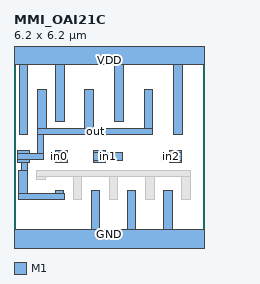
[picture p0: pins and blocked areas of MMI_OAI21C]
MACRO MMI_OAI21C
	CLASS CORE ;
	FOREIGN MMI_OAI21C 0 0 ;
	SIZE 6.2 BY 6.2 ;
	SYMMETRY X Y ;
	SITE CORE1 ;
	PIN out
		DIRECTION output ;
		USE SIGNAL ;
		PORT
			LAYER M1 ;
			RECT 0.765 3.7 1.045 4.98 ;
			LAYER M1 ;
			RECT 2.315 3.7 2.595 4.98 ;
			LAYER M1 ;
			RECT 4.245 3.7 4.525 4.98 ;
			LAYER M1 ;
			RECT 0.765 3.505 4.525 3.7 ;
			LAYER M1 ;
			RECT 0.12 2.885 0.5 2.98 ;
			LAYER M1 ;
			RECT 0.765 2.885 0.955 3.505 ;
			LAYER M1 ;
			RECT 0.12 2.695 0.955 2.885 ;
			LAYER M1 ;
			RECT 0.12 2.6 0.5 2.695 ;
			LAYER M1 ;
			RECT 0.245 2.34 0.435 2.6 ;
			LAYER M1 ;
			RECT 0.16 1.575 0.44 2.34 ;
			LAYER M1 ;
			RECT 1.34 1.575 1.62 1.665 ;
			LAYER M1 ;
			RECT 0.15 1.385 1.64 1.575 ;
		END
		AntennaDiffArea 2.888675 ;
	END out
	PIN in1
		DIRECTION input ;
		USE SIGNAL ;
		PORT
			LAYER M1 ;
			RECT 2.6 2.925 2.98 2.98 ;
			LAYER M1 ;
			RECT 2.6 2.645 3.53 2.925 ;
			LAYER M1 ;
			RECT 2.6 2.6 2.98 2.645 ;
		END
		AntennaGateArea 1.38525 ;
	END in1
	PIN GND
		DIRECTION inout ;
		USE GROUND ;
		PORT
			LAYER M1 ;
			RECT 2.52 0.42 2.8 1.665 ;
			LAYER M1 ;
			RECT 3.7 0.42 3.98 1.665 ;
			LAYER M1 ;
			RECT 4.88 0.42 5.16 1.665 ;
			LAYER M1 ;
			RECT 0 -0.42 6.2 0.42 ;
		END
	END GND
	PIN in2
		DIRECTION input ;
		USE SIGNAL ;
		PORT
			LAYER M1 ;
			RECT 5.08 2.925 5.46 2.98 ;
			LAYER M1 ;
			RECT 4.815 2.645 5.46 2.925 ;
			LAYER M1 ;
			RECT 5.08 2.6 5.46 2.645 ;
		END
		AntennaGateArea 1.38525 ;
	END in2
	PIN VDD
		DIRECTION inout ;
		USE POWER ;
		PORT
			LAYER M1 ;
			RECT 0 5.78 6.2 6.62 ;
			LAYER M1 ;
			RECT 0.175 3.51 0.455 5.78 ;
			LAYER M1 ;
			RECT 1.355 3.92 1.635 5.78 ;
			LAYER M1 ;
			RECT 3.28 3.92 3.56 5.78 ;
			LAYER M1 ;
			RECT 5.21 3.51 5.49 5.78 ;
		END
	END VDD
	PIN in0
		DIRECTION input ;
		USE SIGNAL ;
		PORT
			LAYER M1 ;
			RECT 1.36 2.925 1.74 2.98 ;
			LAYER M1 ;
			RECT 1.2 2.645 1.74 2.925 ;
			LAYER M1 ;
			RECT 1.36 2.6 1.74 2.645 ;
		END
		AntennaGateArea 0.92325 ;
	END in0
	OBS
		LAYER M1 ;
		RECT 0.75 2.15 5.75 2.34 ;
		LAYER M1 ;
		RECT 0.75 2.055 1.03 2.15 ;
		LAYER M1 ;
		RECT 1.93 1.385 2.21 2.15 ;
		LAYER M1 ;
		RECT 3.11 1.385 3.39 2.15 ;
		LAYER M1 ;
		RECT 4.29 1.385 4.57 2.15 ;
		LAYER M1 ;
		RECT 5.47 1.385 5.75 2.15 ;
	END
END MMI_OAI21C
